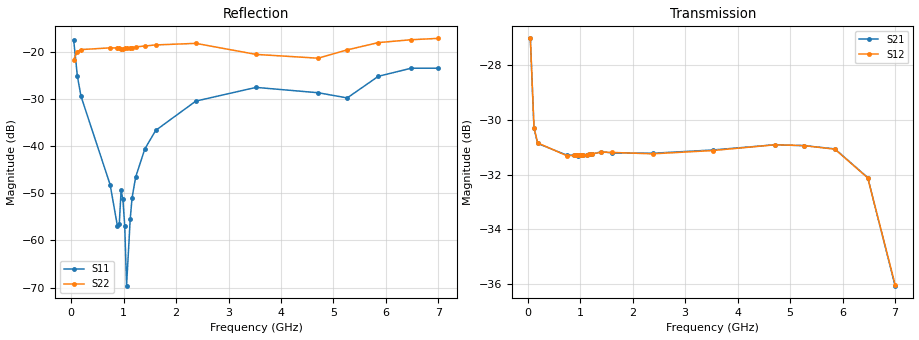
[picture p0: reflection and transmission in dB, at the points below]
! Integrated Device Technology
! Corporate Headquarters
! 6024 Silver Creek Valley Road
! San Jose, CA 95138  USA
! Phone:  1-408-284-8200
! Toll Free:  1-800-223-1366
! Webpage:  http://www.idt.com/
! Timing and RF Division
! 515 Groton Road, Suite 102
! Westford, MA 01886-6024
! Device:  F2258
! Description: Voltage Variable RF Attenuator
! Frequency:  50.0 -  6000.00 MHz
! Package:  3x3 mm Thin QFN Plastic Package: 16 pin
! Ports:  2 RF, 2 DC
!  Pin  1  = NC
!  Pin  2  = NC
!  Pin  3  = RF2  = Port 2
!  Pin  4  = GND
!  Pin  5  = Vdd
!  Pin  6  = NC
!  Pin  7  = VCTRL
!  Pin  8  = NC
!  Pin  9  = GND
!  Pin 10  = RF1  = Port 1
!  Pin 11  = NC
!  Pin 12  = NC
!  Pin 13  = NC
!  Pin 14  = NC
!  Pin 15  = NC
!  Pin 16  = NC
! Vcntrl:  1.710 Volts
! Vdd:  +3.300 Volts
! Current:  1.161 mA
! Data:  The device was measured on a the F2258 evaluation board which has
!  individual transmission lines to the RF pins.  Data was collected
!  using a calibrated network analyzer.  The evaluation board was
!  de-embedded using a TRL calibration technique.
!  The reference plane is the edge of the package pin.
! Misc:  SN 10
!  Action Tracker AT0285
! Date Measured:  2014-12-10
! Date:  2016-01-13  MJV
! Note:
!  Integrated Device Technology supplies this data as a sample of measured
!  data at the package pin for this product.  Your particular data for this
!  product may vary.
!  Data was taken at 25 degrees C.
!  Integrated Device Technology reserves the right to change this data at anytime.
!Freq_(GHz)  S11M_(dB)  S11P_(deg)  S21M_(dB)  S21P_(deg)  S12M_(dB)  S12P_(deg)  S22M_(dB)  S22P_(deg)
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# GHz S dB R 50
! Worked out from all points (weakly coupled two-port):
!   201 points, 50 MHz to 7 GHz, reference 50 ohm
!   highest |S21| = -27.02 dB at 50 MHz (marker M1); lowest = -36.1 dB at 7 GHz (marker M2)
!   lowest |S11| = -69.6 dB at 1.058 GHz (marker M3), VSWR 1.00, Z = 50 + j0.0262 ohm
!   |S11| at or under -10 dB: start of sweep to end of sweep
!   |S22| runs from -22.2 to -17.2 dB; largest |S21 - S12| = 0.00015
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0.05  -17.52 -110.2  -27.02 -53.4  -27.02 -53.4  -21.67 -55.8
0.1195  -25.10 -105.6  -30.30 -28.4  -30.28 -28.4  -20.01 -16.3
0.189  -29.44 -107.5  -30.86 -19.5  -30.84 -19.5  -19.56 -10.4
0.745  -48.20 -131.3  -31.29 -10.4  -31.31 -10.3  -19.19 -8.6
0.884  -56.99 169.6  -31.29 -10.5  -31.30 -10.5  -19.21 -10.3
0.91875  -56.59 140.4  -31.30 -10.6  -31.30 -10.6  -19.22 -10.7
0.9535  -49.41 -152.3  -31.31 -10.7  -31.30 -10.7  -19.44 -9.9
0.98825  -51.32 -165.5  -31.28 -10.8  -31.30 -10.8  -19.43 -10.7
1.023  -56.95 -178.0  -31.28 -10.9  -31.29 -10.9  -19.32 -11.1
1.05775  -69.59 127.8  -31.28 -11.0  -31.29 -11.0  -19.27 -11.2
1.12725  -55.48 59.0  -31.27 -11.2  -31.27 -11.2  -19.17 -12.0
1.162  -51.01 49.0  -31.26 -11.4  -31.26 -11.4  -19.12 -12.2
1.2315  -46.55 35.1  -31.25 -11.8  -31.24 -11.8  -19.00 -12.9
1.40525  -40.62 28.3  -31.16 -13.0  -31.18 -13.0  -18.80 -14.0
1.61375  -36.67 29.3  -31.21 -14.6  -31.19 -14.6  -18.57 -16.2
2.37825  -30.47 46.2  -31.22 -20.2  -31.24 -20.2  -18.24 -21.7
3.525  -27.57 90.8  -31.10 -29.4  -31.12 -29.4  -20.58 -34.5
4.7065  -28.70 95.1  -30.91 -40.4  -30.91 -40.3  -21.38 -58.7
5.2625  -29.80 52.8  -30.94 -46.6  -30.94 -46.6  -19.62 -61.2
5.85325  -25.23 28.9  -31.06 -55.6  -31.07 -55.6  -18.08 -60.6
6.47875  -23.51 40.8  -32.11 -68.9  -32.12 -69.0  -17.47 -77.2
7  -23.50 84.0  -36.06 -69.8  -36.02 -69.6  -17.18 -124.8
